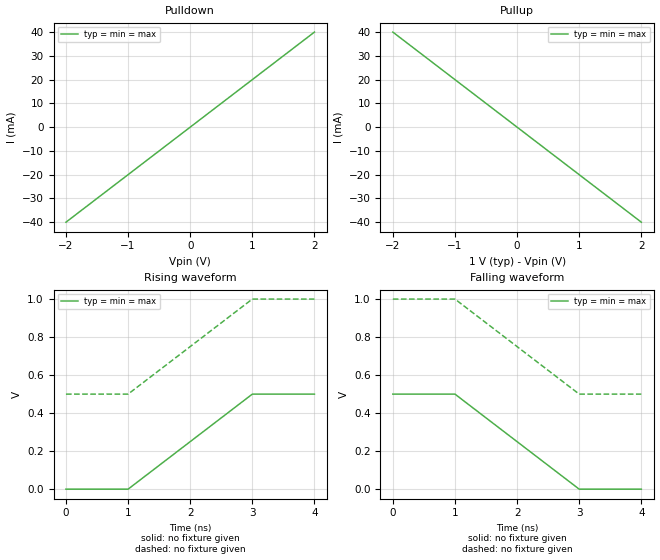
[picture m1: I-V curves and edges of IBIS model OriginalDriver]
| SPDX-License-Identifier: Apache-2.0
| Original SPIKE synthetic arithmetic fixture; no vendor data.
| A 50 ohm signed CMOS driver, zero driver die capacitance, two
| distinct resistive fixtures. Not representative of a commercial device.
[IBIS Ver] 8.0
[File Name] original_cmos.ibs
[File Rev] 1.0
[Component] OriginalFixture
[Manufacturer] SPIKE
[Package]
R_pkg 0.1 0.05 0.2
L_pkg 1n 0.5n 2n
C_pkg 0.5p 0.25p 1p
[Pin] signal_name model_name R_pin L_pin C_pin
1 TX OriginalDriver NA NA NA
2 RX OriginalReceiver NA NA NA
[Model] OriginalReceiver
Model_type Input
C_comp 1p 0.5p 2p
Vinl 0.3
Vinh 0.7
[Voltage Range] 1 1 1
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| Models and submodels in the file (2): OriginalDriver (3-state), OriginalReceiver (Input)
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[Model] OriginalDriver
Model_type 3-state
Polarity Non-Inverting
Enable Active-High
C_comp 0 0 0
[Voltage Range] 1 1 1
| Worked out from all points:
|   slope of the pulldown table from 0 to 0.15 V, typ, clamps not added: 50 ohm
|   slope of the pullup table from 0 to 0.15 V, typ, clamps not added: 50 ohm
|   rising waveform, no fixture given: 20-80 % time 1.2ns typ, 1.2ns min, 1.2ns max; typ from 0 V to 0.5 V
|   rising waveform, no fixture given: 20-80 % time 1.2ns typ, 1.2ns min, 1.2ns max; typ from 0.5 V to 1 V
|   falling waveform, no fixture given: 20-80 % time 1.2ns typ, 1.2ns min, 1.2ns max; typ from 0.5 V to 0 V
|   falling waveform, no fixture given: 20-80 % time 1.2ns typ, 1.2ns min, 1.2ns max; typ from 1 V to 0.5 V
[Pullup]
-2V       40mA       40mA       40mA
0V        0A         0A         0A
2V        -40mA      -40mA      -40mA
[Pulldown]
-2V       -40mA      -40mA      -40mA
0V        0A         0A         0A
2V        40mA       40mA       40mA
[GND Clamp]
-2V       0A         0A         0A
2V        0A         0A         0A
[POWER Clamp]
-2V       0A         0A         0A
2V        0A         0A         0A
[Rising Waveform]
R_fixture 50
V_fixture 0
V_fixture_min 0
V_fixture_max 0
0s        0V         0V         0V
1ns       0V         0V         0V
2ns       250mV      250mV      250mV
3ns       500mV      500mV      500mV
4ns       500mV      500mV      500mV
[Rising Waveform]
R_fixture 50
V_fixture 1
V_fixture_min 1
V_fixture_max 1
0s        500mV      500mV      500mV
1ns       500mV      500mV      500mV
2ns       750mV      750mV      750mV
3ns       1V         1V         1V
4ns       1V         1V         1V
[Falling Waveform]
R_fixture 50
V_fixture 0
V_fixture_min 0
V_fixture_max 0
0s        500mV      500mV      500mV
1ns       500mV      500mV      500mV
2ns       250mV      250mV      250mV
3ns       0V         0V         0V
4ns       0V         0V         0V
[Falling Waveform]
R_fixture 50
V_fixture 1
V_fixture_min 1
V_fixture_max 1
0s        1V         1V         1V
1ns       1V         1V         1V
2ns       750mV      750mV      750mV
3ns       500mV      500mV      500mV
4ns       500mV      500mV      500mV
